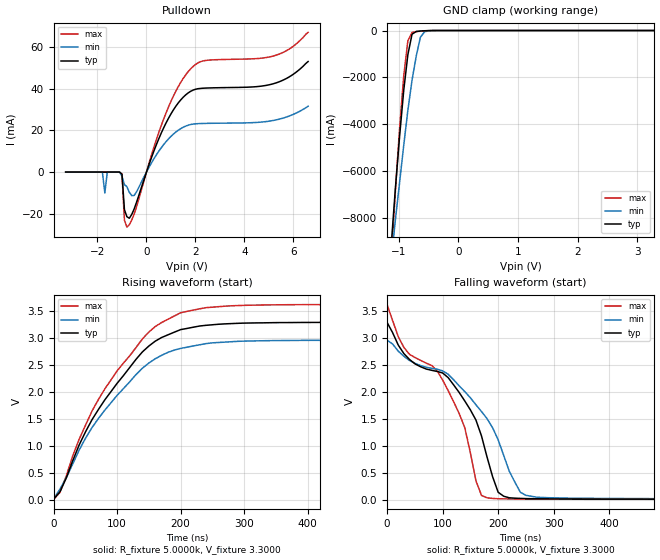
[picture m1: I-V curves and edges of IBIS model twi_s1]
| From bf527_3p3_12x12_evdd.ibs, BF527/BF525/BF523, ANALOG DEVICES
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|   Model ptwi400kv123
[Model]   twi_s1
Model_type I/O_open_drain
Polarity   Non-Inverting
Enable   Active-Low
Vinl =   0.9900V
Vinh =   2.3100V
Vmeas =  1.6500V
Cref =   50.0000pF
Rref =   5.0000k
Vref =   3.3000V
C_comp   7.1300pF   6.4200pF   7.8500pF
[Temperature Range]   25.0000   0.1250k   0.0
[Voltage Range]   3.3000V   2.9700V   3.6300V
[Pullup Reference]   3.3000V   2.9700V   3.6300V
[Pulldown Reference]   0.0V   0.0V   0.0V
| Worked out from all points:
|   slope of the pulldown table from 0 to 0.495 V, typ, clamps not added: 31.4 ohm
|   GND clamp passes 1 mA (typ) near -0.44 V on its own axis
|   rising waveform, R_fixture 5.0000k, V_fixture 3.3000: 20-80 % time 104ns typ, 106ns min, 107ns max; typ from 0.019 V to 3.3 V
|   falling waveform, R_fixture 5.0000k, V_fixture 3.3000: 20-80 % time 146ns typ, 114ns min, 126ns max; typ from 3.3 V to 0.019 V
[Pulldown]
|Voltage   I(typ)   I(min)   I(max)
-3.3V     0A         0A         0A
-1.8V     0A         0A         0A
-1.7V     0A         -10mA      0A
-1.6V     0A         0A         0A
-1V       -1mA       -2mA       -1mA
-900mV    -18mA      -6mA       -23mA
-800mV    -21.4mA    -7mA       -26.4mA
-500mV    -17.59mA   -11.2mA    -20.02mA
800mV     23.57mA    14.59mA    28.39mA
1.8V      38.7mA     22.79mA    49.44mA
5.1V      42.1mA     24.59mA    55.41mA
6.6V      53mA       31.57mA    67mA
[GND_clamp]
|Voltage   I(typ)   I(min)   I(max)
-3.3V     -90.22A    -67.03A    -109.2A
-1.13V    -9.15A     -9.802A    -9.773A
-1.06V    -6.741A    -8.07A     -6.847A
-990mV    -4.542A    -6.502A    -4.203A
-920mV    -2.558A    -4.904A    -1.946A
-850mV    -1.03A     -3.397A    -436.4mA
-780mV    -157.1mA   -2.116A    -83.33mA
-710mV    -41.57mA   -1.097A    -46.35mA
-640mV    -20.93mA   -289.8mA   -29.13mA
-570mV    -10.16mA   -55.23mA   -15.76mA
-500mV    -3.553mA   -11.78mA   -6.312mA
3.28V     9.333nA    34.31nA    22.33nA
[Ramp]
| variable   typ   min   max
dV/dt_r  1.9683/0.1040u   1.7657/0.1065u   2.1669/0.1069u
dV/dt_f  1.9682/0.1464u   1.7655/0.1144u   2.1669/0.1264u
R_load = 5.0000k
[Rising Waveform]
R_fixture= 5.0000k
V_fixture= 3.3000
V_fixture_min= 2.9700
V_fixture_max= 3.6300
L_fixture= 0.0H
C_fixture= 0.0F
|time   V(typ)   V(min)   V(max)
0s        18.51mV    26.09mV    17.45mV
10.1ns    156.9mV    206.3mV    144.4mV
40.4ns    1.026V     931.6mV    1.132V
60.61ns   1.494V     1.347V     1.654V
100ns     2.166V     1.943V     2.397V
150ns     2.858V     2.543V     3.117V
200ns     3.163V     2.815V     3.475V
240ns     3.243V     2.904V     3.57V
330ns     3.289V     2.957V     3.62V
1us       3.299V     2.969V     3.629V
[Falling Waveform]
R_fixture= 5.0000k
V_fixture= 3.3000
V_fixture_min= 2.9700
V_fixture_max= 3.6300
L_fixture= 0.0H
C_fixture= 0.0F
|time   V(typ)   V(min)   V(max)
0s        3.299V     2.969V     3.629V
30.3ns    2.719V     2.67V      2.834V
110ns     2.274V     2.336V     2.034V
140ns     1.839V     2.013V     1.343V
160ns     1.487V     1.77V      361.3mV
180ns     800.6mV    1.513V     45.17mV
200ns     148.5mV    1.121V     28.15mV
220ns     46.22mV    538.2mV    24.99mV
250ns     30.66mV    91.34mV    21.99mV
1us       18.65mV    26.53mV    17.55mV
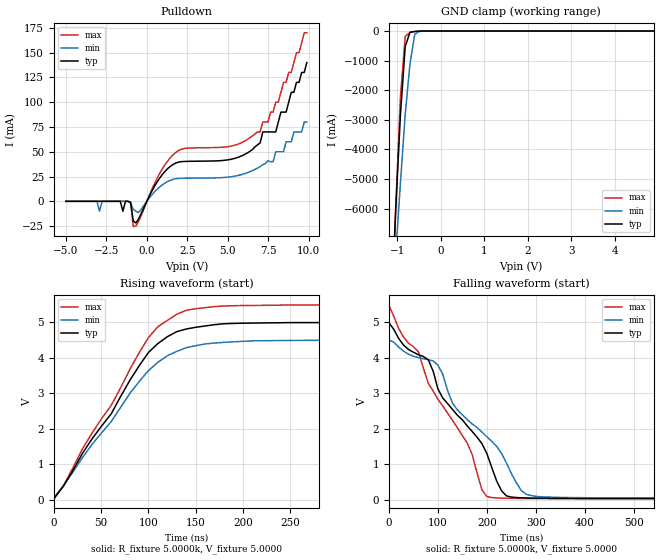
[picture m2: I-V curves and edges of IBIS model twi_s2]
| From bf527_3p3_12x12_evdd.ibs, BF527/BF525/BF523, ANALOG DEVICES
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[Model]   twi_s2
Model_type I/O_open_drain
Polarity   Non-Inverting
Enable   Active-Low
Vinl =   1.5000V
Vinh =   3.5000V
Vmeas =  2.5000V
Cref =   50.0000pF
Rref =   5.0000k
Vref =   5.0000V
C_comp   7.1300pF   6.4200pF   7.8500pF
[Temperature Range]   25.0000   0.1250k   0.0
[Voltage Range]   5.0000V   4.5000V   5.5000V
[Pullup Reference]   5.0000V   4.5000V   5.5000V
[Pulldown Reference]   0.0V   0.0V   0.0V
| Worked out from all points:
|   slope of the pulldown table from 0 to 0.75 V, typ, clamps not added: 33.5 ohm
|   GND clamp passes 1 mA (typ) near -0.41 V on its own axis
|   rising waveform, R_fixture 5.0000k, V_fixture 5.0000: 20-80 % time 71.7ns typ, 74.9ns min, 71.7ns max; typ from 0.028 V to 5 V
|   falling waveform, R_fixture 5.0000k, V_fixture 5.0000: 20-80 % time 133ns typ, 136ns min, 131ns max; typ from 5 V to 0.028 V
[Pulldown]
|Voltage   I(typ)   I(min)   I(max)
-5V       0A         0A         0A
-3.08V    0A         0A         0A
-2.92V    0A         -10mA      0A
-1.48V    -10mA      0A         0A
-1.16V    0A         0A         0A
-680mV    -21.84mA   -10mA      -24.85mA
760mV     22.63mA    14.03mA    27.21mA
1.88V     39.19mA    22.97mA    50.38mA
5.24V     42.56mA    24.89mA    55.85mA
7V        59mA       35mA       70mA
7.96V     70mA       50mA       100mA
9.88V     140mA      80mA       170mA
[GND_clamp]
|Voltage   I(typ)   I(min)   I(max)
-5V       -154.8A    -112.6A    -188.3A
-1.15V    -9.852A    -10.3A     -10.62A
-1.04V    -6.072A    -7.584A    -6.041A
-930mV    -2.823A    -5.131A    -2.23A
-820mV    -522mA     -2.814A    -178.4mA
-710mV    -41.57mA   -1.097A    -46.35mA
-600mV    -14.23mA   -109.6mA   -21.06mA
-490mV    -2.941mA   -9.414mA   -5.34mA
4.9V      652.3nA    550nA      1.064uA
[Ramp]
| variable   typ   min   max
dV/dt_r  2.9801/71.5841n   2.6744/75.0558n   3.2775/71.5341n
dV/dt_f  2.9806/0.1337u   2.6745/0.1359u   3.2775/0.1317u
R_load = 5.0000k
[Rising Waveform]
R_fixture= 5.0000k
V_fixture= 5.0000
V_fixture_min= 4.5000
V_fixture_max= 5.5000
L_fixture= 0.0H
C_fixture= 0.0F
|time   V(typ)   V(min)   V(max)
0s        28.11mV    39.66mV    26.48mV
10.1ns    376.6mV    399.7mV    388.8mV
40.4ns    1.714V     1.559V     1.878V
60.61ns   2.418V     2.199V     2.657V
80.81ns   3.385V     3.013V     3.697V
100ns     4.15V      3.639V     4.568V
110ns     4.402V     3.874V     4.878V
140ns     4.81V      4.284V     5.338V
230ns     4.984V     4.483V     5.48V
1us       4.995V     4.497V     5.489V
[Falling Waveform]
R_fixture= 5.0000k
V_fixture= 5.0000
V_fixture_min= 4.5000
V_fixture_max= 5.5000
L_fixture= 0.0H
C_fixture= 0.0F
|time   V(typ)   V(min)   V(max)
0s        4.996V     4.498V     5.489V
60.61ns   4.086V     4.002V     4.163V
80.81ns   3.941V     3.943V     3.274V
100ns     3.132V     3.794V     2.835V
130ns     2.541V     2.72V      2.236V
200ns     1.299V     1.77V      86.97mV
240ns     105.5mV    1.034V     39.25mV
270ns     52.18mV    258.9mV    33.25mV
300ns     42.03mV    90.55mV    31.18mV
1us       28.31mV    40.48mV    26.54mV
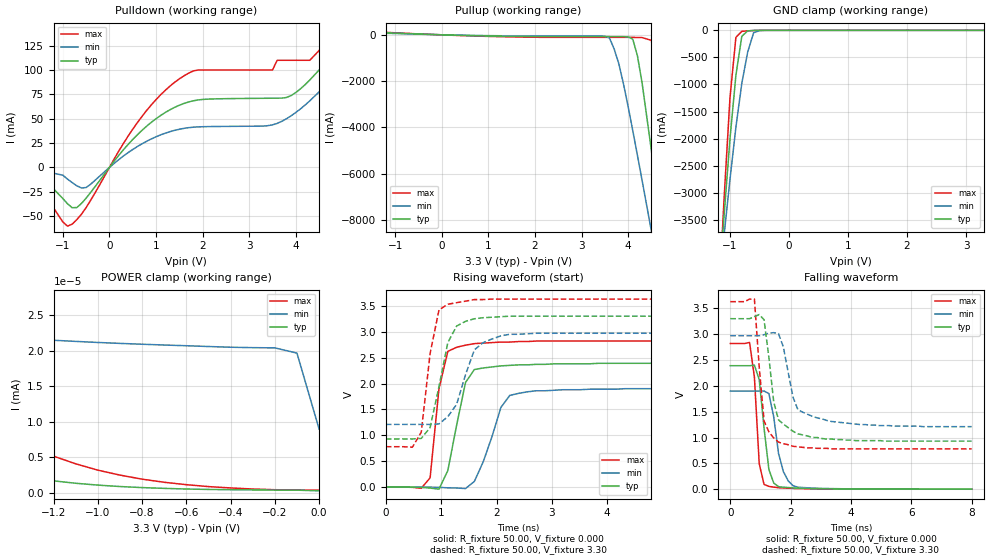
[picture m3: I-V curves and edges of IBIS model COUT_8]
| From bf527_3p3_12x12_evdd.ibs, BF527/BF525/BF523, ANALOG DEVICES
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|   Model prw0408swcdg_25
[Model]   COUT_8
Model_type   I/O
Polarity   Non-Inverting
Enable   Active-Low
Vinl =   0.40V
Vinh =   2.40V
Vmeas =   1.20V
Cref =  50.00pF
Rref =   1.00M
Vref =  0.000V
C_comp   4.60pF   4.14pF   5.06pF
[Temperature Range]   25.00   0.12k   -40.00
[Voltage Range]   3.30V   2.97V   3.63V
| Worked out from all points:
|   slope of the pulldown table from 0 to 0.495 V, typ, clamps not added: 17.4 ohm
|   slope of the pullup table from 0 to 0.495 V, typ, clamps not added: 17.2 ohm
|   GND clamp passes 1 mA (typ) near -0.53 V on its own axis
|   POWER clamp passes 1 mA (typ) near -3.01 V on its own axis
|   rising waveform, R_fixture 50.00, V_fixture 0.000: 20-80 % time 270ps typ, 361ps min, 203ps max; typ from 0 V to 2.39 V
|   rising waveform, R_fixture 50.00, V_fixture 3.30: 20-80 % time 287ps typ, 335ps min, 221ps max; typ from 0.93 V to 3.3 V
|   falling waveform, R_fixture 50.00, V_fixture 0.000: 20-80 % time 265ps typ, 344ps min, 173ps max; typ from 2.39 V to 0 V
|   falling waveform, R_fixture 50.00, V_fixture 3.30: 20-80 % time 351ps typ, 422ps min, 240ps max; typ from 3.3 V to 0.93 V
[Pulldown]
| voltage   I(typ)   I(min)   I(max)
-3.3V     0A         0A         0A
-1.7V     0A         0A         -10mA
-900mV    -37.3mA    -12mA      -60.3mA
-500mV    -31.56mA   -20.64mA   -41.25mA
700mV     38.11mA    24.26mA    52.44mA
1.7V      67.22mA    40.81mA    96.76mA
3.9V      73.78mA    52.99mA    110mA
4.3V      89.73mA    68.32mA    110mA
5.1V      140mA      110mA      170mA
5.5V      170mA      59.39mA    210mA
6.1V      130mA      60.53mA    270mA
6.6V      900mA      68.68mA    3.72A
[Pullup]
| voltage   I(typ)   I(min)   I(max)
-3.3V     29.4mA     8.69mA     100mA
-2.5V     150mA      14.55mA    190mA
3.6V      -78.87mA   -140mA     -110mA
3.8V      -79.53mA   -1.25A     -110mA
4.1V      -190mA     -4.14A     -110mA
4.2V      -910mA     -5.21A     -120mA
4.3V      -2.08A     -6.29A     -120mA
4.5V      -5A        -8.48A     -240mA
4.7V      -8.09A     -10.68A    -3.22A
4.9V      -11.24A    -12.9A     -7.47A
5.1V      -14.4A     -15.12A    -11.86A
6.6V      -38.32A    -31.88A    -44.78A
[GND_clamp]
| voltage   I(typ)   I(min)   I(max)
-3.3V     -38.23A    -28.13A    -52.07A
-1.2V     -4.92A     -4.84A     -5.19A
-1.1V     -3.42A     -3.78A     -3.1A
-1V       -2A        -2.75A     -1.24A
-900mV    -830mA     -1.79A     -130mA
-800mV    -110mA     -980mA     -19.34mA
-700mV    -10.17mA   -400mA     -9.85mA
-600mV    -2.61mA    -45.18mA   -3.52mA
-500mV    -460uA     -4.57mA    -550uA
3.3V      270pA      20.45nA    210pA
[POWER_clamp]
| voltage   I(typ)   I(min)   I(max)
-3.3V     770mA      230nA      7.24A
-2.6V     27.11nA    32.42nA    2.22mA
-2.4V     19.51nA    28.98nA    180nA
-2.1V     11.42nA    25.47nA    30.02nA
-2V       9.44nA     24.65nA    25.41nA
-1.7V     5.12nA     22.9nA     14.8nA
-1.5V     3.3nA      22.17nA    9.95nA
-1.3V     2.1nA      21.67nA    6.47nA
-800mV    730pA      20.92nA    1.92nA
-200mV    380pA      20.41nA    430pA
-100mV    370pA      19.67nA    390pA
0V        270pA      8.98nA     360pA
[Ramp]
| variable   typ   min   max
dV/dt_r   1.43/0.21n   1.14/0.34n   1.69/0.14n
dV/dt_f   1.42/0.33n   1.06/0.46n   1.71/0.21n
R_load = 50.00
[Rising Waveform]
R_fixture = 50.00
V_fixture = 0.000
V_fixture_min = 0.000
V_fixture_max = 0.000
L_fixture = 0.000H
C_fixture = 0.000F
| time   V(typ)   V(min)   V(max)
0s        0V         0V         0V
800ps     -18.52mV   -880uV     180mV
960ps     -39.4mV    -4.85mV    1.9V
1.12ns    320mV      -13.43mV   2.62V
1.28ns    1.2V       -17.16mV   2.7V
1.44ns    2.02V      -27.53mV   2.74V
1.6ns     2.27V      110mV      2.77V
2.08ns    2.34V      1.54V      2.8V
2.24ns    2.35V      1.77V      2.8V
8ns       2.39V      1.9V       2.82V
[Rising Waveform]
R_fixture = 50.00
V_fixture = 3.30
V_fixture_min = 2.97
V_fixture_max = 3.63
L_fixture = 0.000H
C_fixture = 0.000F
| time   V(typ)   V(min)   V(max)
0s        930mV      1.21V      780mV
480ps     930mV      1.21V      770mV
640ps     940mV      1.21V      1.06V
800ps     1.15V      1.21V      2.58V
960ps     1.94V      1.22V      3.42V
1.12ns    2.79V      1.36V      3.53V
1.28ns    3.11V      1.6V       3.56V
1.6ns     3.25V      2.65V      3.62V
2.08ns    3.29V      2.92V      3.63V
8ns       3.3V       2.97V      3.63V
[Falling Waveform]
R_fixture = 50.00
V_fixture = 0.000
V_fixture_min = 0.000
V_fixture_max = 0.000
L_fixture = 0.000H
C_fixture = 0.000F
| time   V(typ)   V(min)   V(max)
0s        2.39V      1.9V       2.82V
640ps     2.39V      1.9V       2.84V
800ps     2.4V       1.9V       2.17V
960ps     2.12V      1.9V       490mV
1.12ns    1.18V      1.9V       91.85mV
1.28ns    380mV      1.85V      54.33mV
1.44ns    120mV      1.4V       39.26mV
1.76ns    38.11mV    340mV      23.2mV
2.08ns    23.9mV     67.58mV    15.25mV
8ns       15.47uV    140uV      4.83uV
[Falling Waveform]
R_fixture = 50.00
V_fixture = 3.30
V_fixture_min = 2.97
V_fixture_max = 3.63
L_fixture = 0.000H
C_fixture = 0.000F
| time   V(typ)   V(min)   V(max)
0s        3.3V       2.97V      3.63V
800ps     3.34V      2.97V      3.68V
1.12ns    3.28V      2.99V      1.32V
1.44ns    1.69V      3.03V      990mV
1.6ns     1.34V      3.01V      910mV
1.76ns    1.26V      2.75V      880mV
2.08ns    1.12V      1.78V      830mV
2.4ns     1.05V      1.49V      810mV
4.32ns    940mV      1.25V      780mV
8ns       930mV      1.21V      780mV
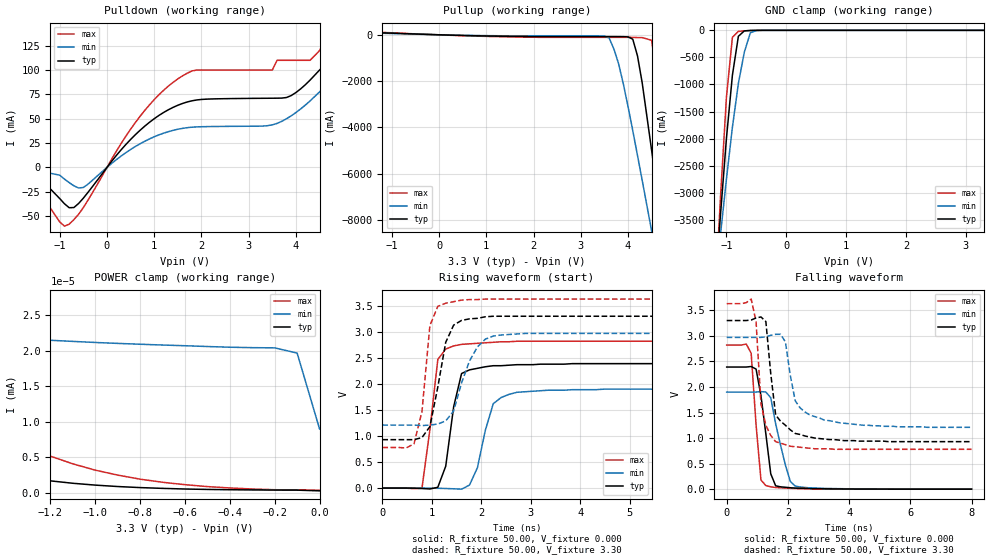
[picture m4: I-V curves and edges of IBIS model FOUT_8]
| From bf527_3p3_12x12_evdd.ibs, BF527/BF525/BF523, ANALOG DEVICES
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|   Model prw0408swcdg_3v_25
[Model]   FOUT_8
Model_type   I/O
Polarity   Non-Inverting
Enable   Active-Low
Vinl =   0.40V
Vinh =   2.40V
Vmeas =   1.20V
Cref =  50.00pF
Rref =   1.00M
Vref =  0.000V
C_comp   4.85pF   4.36pF   5.33pF
[Temperature Range]   25.00   0.12k   -40.00
[Voltage Range]   3.30V   2.97V   3.63V
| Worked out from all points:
|   slope of the pulldown table from 0 to 0.495 V, typ, clamps not added: 17.4 ohm
|   slope of the pullup table from 0 to 0.495 V, typ, clamps not added: 17.2 ohm
|   GND clamp passes 1 mA (typ) near -0.53 V on its own axis
|   POWER clamp passes 1 mA (typ) near -3.01 V on its own axis
|   rising waveform, R_fixture 50.00, V_fixture 0.000: 20-80 % time 240ps typ, 293ps min, 214ps max; typ from 0 V to 2.39 V
|   rising waveform, R_fixture 50.00, V_fixture 3.30: 20-80 % time 285ps typ, 401ps min, 185ps max; typ from 0.93 V to 3.3 V
|   falling waveform, R_fixture 50.00, V_fixture 0.000: 20-80 % time 309ps typ, 440ps min, 217ps max; typ from 2.39 V to 0 V
|   falling waveform, R_fixture 50.00, V_fixture 3.30: 20-80 % time 310ps typ, 472ps min, 260ps max; typ from 3.3 V to 0.93 V
[Pulldown]
| voltage   I(typ)   I(min)   I(max)
-3.3V     0A         0A         0A
-1.7V     0A         0A         -10mA
-900mV    -37.3mA    -12mA      -60.3mA
-500mV    -31.56mA   -20.64mA   -41.25mA
700mV     38.11mA    24.26mA    52.44mA
1.7V      67.22mA    40.81mA    96.76mA
3.9V      73.78mA    52.99mA    110mA
4.3V      89.73mA    68.32mA    110mA
5.1V      140mA      110mA      170mA
5.5V      170mA      59.39mA    210mA
6.1V      130mA      60.53mA    270mA
6.6V      900mA      68.68mA    3.72A
[Pullup]
| voltage   I(typ)   I(min)   I(max)
-3.3V     29.4mA     8.69mA     100mA
-2.5V     150mA      14.55mA    190mA
3.6V      -78.87mA   -140mA     -110mA
3.8V      -79.53mA   -1.25A     -110mA
4.1V      -190mA     -4.14A     -110mA
4.2V      -910mA     -5.21A     -120mA
4.3V      -2.08A     -6.29A     -120mA
4.5V      -5A        -8.48A     -240mA
4.7V      -8.09A     -10.68A    -3.22A
4.9V      -11.24A    -12.9A     -7.47A
5.1V      -14.4A     -15.12A    -11.86A
6.6V      -38.32A    -31.88A    -44.78A
[GND_clamp]
| voltage   I(typ)   I(min)   I(max)
-3.3V     -38.23A    -28.13A    -52.07A
-1.2V     -4.92A     -4.84A     -5.19A
-1.1V     -3.42A     -3.78A     -3.1A
-1V       -2A        -2.75A     -1.24A
-900mV    -830mA     -1.79A     -130mA
-800mV    -110mA     -980mA     -19.34mA
-700mV    -10.17mA   -400mA     -9.85mA
-600mV    -2.61mA    -45.18mA   -3.52mA
-500mV    -460uA     -4.57mA    -550uA
3.3V      270pA      20.45nA    210pA
[POWER_clamp]
| voltage   I(typ)   I(min)   I(max)
-3.3V     770mA      230nA      7.24A
-2.6V     27.11nA    32.42nA    2.22mA
-2.4V     19.51nA    28.98nA    180nA
-2.1V     11.42nA    25.47nA    30.02nA
-2V       9.44nA     24.65nA    25.41nA
-1.7V     5.12nA     22.9nA     14.8nA
-1.5V     3.3nA      22.17nA    9.95nA
-1.3V     2.1nA      21.67nA    6.47nA
-800mV    730pA      20.92nA    1.92nA
-200mV    380pA      20.41nA    430pA
-100mV    370pA      19.67nA    390pA
0V        270pA      8.98nA     360pA
[Ramp]
| variable   typ   min   max
dV/dt_r   1.43/0.21n   1.14/0.35n   1.69/0.15n
dV/dt_f   1.42/0.31n   1.06/0.48n   1.71/0.21n
R_load = 50.00
[Rising Waveform]
R_fixture = 50.00
V_fixture = 0.000
V_fixture_min = 0.000
V_fixture_max = 0.000
L_fixture = 0.000H
C_fixture = 0.000F
| time   V(typ)   V(min)   V(max)
0s        0V         0V         0V
800ps     -8.44mV    -70.12uV   -2.49mV
1.12ns    15.09mV    -4.13mV    2.47V
1.28ns    420mV      -8.02mV    2.67V
1.44ns    1.56V      -13.76mV   2.73V
1.6ns     2.2V       -20.86mV   2.76V
1.92ns    2.3V       390mV      2.78V
2.24ns    2.35V      1.62V      2.8V
2.56ns    2.36V      1.8V       2.81V
8ns       2.39V      1.9V       2.82V
[Rising Waveform]
R_fixture = 50.00
V_fixture = 3.30
V_fixture_min = 2.97
V_fixture_max = 3.63
L_fixture = 0.000H
C_fixture = 0.000F
| time   V(typ)   V(min)   V(max)
0s        930mV      1.21V      780mV
640ps     930mV      1.21V      850mV
800ps     970mV      1.2V       1.47V
960ps     1.18V      1.21V      3.12V
1.12ns    1.94V      1.23V      3.49V
1.28ns    2.8V       1.29V      3.55V
1.44ns    3.13V      1.48V      3.58V
1.76ns    3.25V      2.44V      3.62V
2.24ns    3.3V       2.92V      3.63V
8ns       3.3V       2.97V      3.63V
[Falling Waveform]
R_fixture = 50.00
V_fixture = 0.000
V_fixture_min = 0.000
V_fixture_max = 0.000
L_fixture = 0.000H
C_fixture = 0.000F
| time   V(typ)   V(min)   V(max)
0s        2.39V      1.9V       2.82V
800ps     2.4V       1.9V       2.66V
960ps     2.35V      1.9V       1.26V
1.12ns    1.83V      1.91V      180mV
1.28ns    1.08V      1.9V       70.27mV
1.44ns    300mV      1.79V      45.97mV
1.6ns     66.01mV    1.28V      32.22mV
2.08ns    27.62mV    150mV      17.01mV
2.24ns    21.21mV    60.02mV    12.92mV
8ns       50.75uV    170uV      16.89uV
[Falling Waveform]
R_fixture = 50.00
V_fixture = 3.30
V_fixture_min = 2.97
V_fixture_max = 3.63
L_fixture = 0.000H
C_fixture = 0.000F
| time   V(typ)   V(min)   V(max)
0s        3.3V       2.97V      3.63V
800ps     3.31V      2.97V      3.72V
960ps     3.35V      2.97V      3.28V
1.12ns    3.37V      2.97V      1.67V
1.28ns    3.28V      2.98V      1.25V
1.6ns     1.45V      3.03V      930mV
1.92ns    1.25V      2.88V      870mV
2.24ns    1.09V      1.73V      830mV
2.72ns    1.02V      1.45V      800mV
8ns       930mV      1.21V      780mV
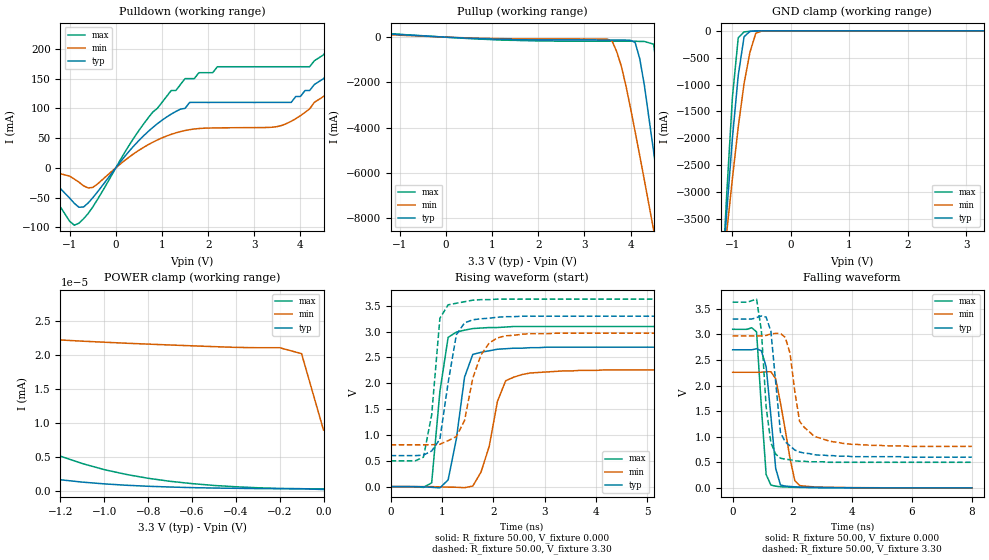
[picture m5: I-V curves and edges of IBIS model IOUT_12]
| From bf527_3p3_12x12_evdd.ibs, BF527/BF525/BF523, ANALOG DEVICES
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|   Model prw0812swcdg_25
[Model]   IOUT_12
Model_type   I/O
Polarity   Non-Inverting
Enable   Active-Low
Vinl =   0.40V
Vinh =   2.40V
Vmeas =   1.20V
Cref =  50.00pF
Rref =   1.00M
Vref =  0.000V
C_comp   4.38pF   3.94pF   4.82pF
[Temperature Range]   25.00   0.12k   -40.00
[Voltage Range]   3.30V   2.97V   3.63V
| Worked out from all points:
|   slope of the pulldown table from 0 to 0.495 V, typ, clamps not added: 10.9 ohm
|   slope of the pullup table from 0 to 0.495 V, typ, clamps not added: 10.8 ohm
|   GND clamp passes 1 mA (typ) near -0.53 V on its own axis
|   POWER clamp passes 1 mA (typ) near -3.01 V on its own axis
|   rising waveform, R_fixture 50.00, V_fixture 0.000: 20-80 % time 252ps typ, 328ps min, 208ps max; typ from 0 V to 2.7 V
|   rising waveform, R_fixture 50.00, V_fixture 3.30: 20-80 % time 257ps typ, 335ps min, 190ps max; typ from 0.6 V to 3.3 V
|   falling waveform, R_fixture 50.00, V_fixture 0.000: 20-80 % time 260ps typ, 414ps min, 214ps max; typ from 2.7 V to 0 V
|   falling waveform, R_fixture 50.00, V_fixture 3.30: 20-80 % time 262ps typ, 378ps min, 256ps max; typ from 3.3 V to 0.6 V
[Pulldown]
| voltage   I(typ)   I(min)   I(max)
-3.3V     0A         0A         0A
-2.1V     0A         0A         0A
-900mV    -59.7mA    -19mA      -96.5mA
-500mV    -50.5mA    -33.03mA   -66mA
600mV     53.68mA    34.3mA     73.6mA
1.5V      100mA      62.7mA     150mA
3.8V      110mA      78.23mA    170mA
5.1V      210mA      170mA      260mA
5.5V      260mA      93.56mA    320mA
5.9V      300mA      93.14mA    380mA
6.1V      200mA      95.36mA    410mA
6.6V      960mA      110mA      3.88A
[Pullup]
| voltage   I(typ)   I(min)   I(max)
-3.3V     42.4mA     12.36mA    140mA
-2.3V     220mA      140mA      260mA
3.6V      -130mA     -170mA     -180mA
3.8V      -130mA     -1.28A     -180mA
4.1V      -240mA     -4.18A     -180mA
4.2V      -960mA     -5.24A     -190mA
4.3V      -2.13A     -6.32A     -190mA
4.5V      -5.05A     -8.51A     -310mA
4.7V      -8.14A     -10.71A    -3.29A
4.9V      -11.28A    -12.93A    -7.53A
5.1V      -14.45A    -15.15A    -11.93A
6.6V      -38.37A    -31.91A    -44.86A
[GND_clamp]
| voltage   I(typ)   I(min)   I(max)
-3.3V     -38.23A    -28.13A    -52.07A
-1.2V     -4.92A     -4.84A     -5.19A
-1.1V     -3.42A     -3.78A     -3.1A
-1V       -2A        -2.75A     -1.24A
-900mV    -830mA     -1.79A     -130mA
-800mV    -110mA     -980mA     -19.34mA
-700mV    -10.17mA   -400mA     -9.85mA
-600mV    -2.61mA    -45.18mA   -3.52mA
-500mV    -460uA     -4.57mA    -550uA
3.3V      270pA      21.08nA    210pA
[POWER_clamp]
| voltage   I(typ)   I(min)   I(max)
-3.3V     770mA      230nA      7.24A
-2.7V     34.09nA    35.52nA    160mA
-2.6V     27.14nA    33.37nA    2.22mA
-2.4V     19.53nA    29.9nA     180nA
-2.3V     16.45nA    28.52nA    42.13nA
-2.1V     11.45nA    26.35nA    30.02nA
-1.7V     5.14nA     23.72nA    14.8nA
-1.3V     2.12nA     22.43nA    6.47nA
-800mV    750pA      21.61nA    1.92nA
-200mV    390pA      21.08nA    430pA
-100mV    390pA      20.21nA    390pA
0V        270pA      8.99nA     360pA
[Ramp]
| variable   typ   min   max
dV/dt_r   1.62/0.20n   1.36/0.32n   1.86/0.14n
dV/dt_f   1.62/0.27n   1.30/0.42n   1.88/0.22n
R_load = 50.00
[Rising Waveform]
R_fixture = 50.00
V_fixture = 0.000
V_fixture_min = 0.000
V_fixture_max = 0.000
L_fixture = 0.000H
C_fixture = 0.000F
| time   V(typ)   V(min)   V(max)
0s        0V         0V         0V
800ps     -13.46mV   -850uV     72.97mV
960ps     -24.1mV    -4.43mV    1.84V
1.12ns    130mV      -10.9mV    2.89V
1.28ns    920mV      -12.29mV   2.99V
1.44ns    2.12V      -20.87mV   3.03V
1.6ns     2.56V      10.64mV    3.06V
2.08ns    2.66V      1.65V      3.08V
2.4ns     2.68V      2.12V      3.1V
8ns       2.7V       2.26V      3.1V
[Rising Waveform]
R_fixture = 50.00
V_fixture = 3.30
V_fixture_min = 2.97
V_fixture_max = 3.63
L_fixture = 0.000H
C_fixture = 0.000F
| time   V(typ)   V(min)   V(max)
0s        600mV      810mV      500mV
640ps     610mV      810mV      570mV
800ps     690mV      810mV      1.39V
960ps     920mV      820mV      3.26V
1.12ns    2.01V      890mV      3.52V
1.28ns    2.94V      970mV      3.55V
1.44ns    3.17V      1.28V      3.58V
1.76ns    3.25V      2.55V      3.62V
2.08ns    3.28V      2.88V      3.63V
8ns       3.3V       2.97V      3.63V
[Falling Waveform]
R_fixture = 50.00
V_fixture = 0.000
V_fixture_min = 0.000
V_fixture_max = 0.000
L_fixture = 0.000H
C_fixture = 0.000F
| time   V(typ)   V(min)   V(max)
0s        2.7V       2.26V      3.1V
800ps     2.72V      2.26V      3.05V
960ps     2.68V      2.26V      1.59V
1.12ns    2.37V      2.27V      260mV
1.28ns    1.4V       2.27V      54.52mV
1.44ns    380mV      2.13V      32.27mV
1.6ns     55.65mV    1.66V      20.93mV
2.08ns    19.73mV    140mV      10.7mV
2.24ns    15.27mV    45.09mV    8.29mV
8ns       31.18uV    120uV      -980nV
[Falling Waveform]
R_fixture = 50.00
V_fixture = 3.30
V_fixture_min = 2.97
V_fixture_max = 3.63
L_fixture = 0.000H
C_fixture = 0.000F
| time   V(typ)   V(min)   V(max)
0s        3.3V       2.97V      3.63V
800ps     3.33V      2.97V      3.69V
960ps     3.36V      2.97V      3.08V
1.12ns    3.34V      2.98V      1.58V
1.28ns    3.06V      3.01V      880mV
1.6ns     1.08V      3.02V      580mV
1.92ns    820mV      2.63V      550mV
2.24ns    700mV      1.3V       520mV
2.72ns    650mV      1.01V      510mV
8ns       600mV      810mV      500mV
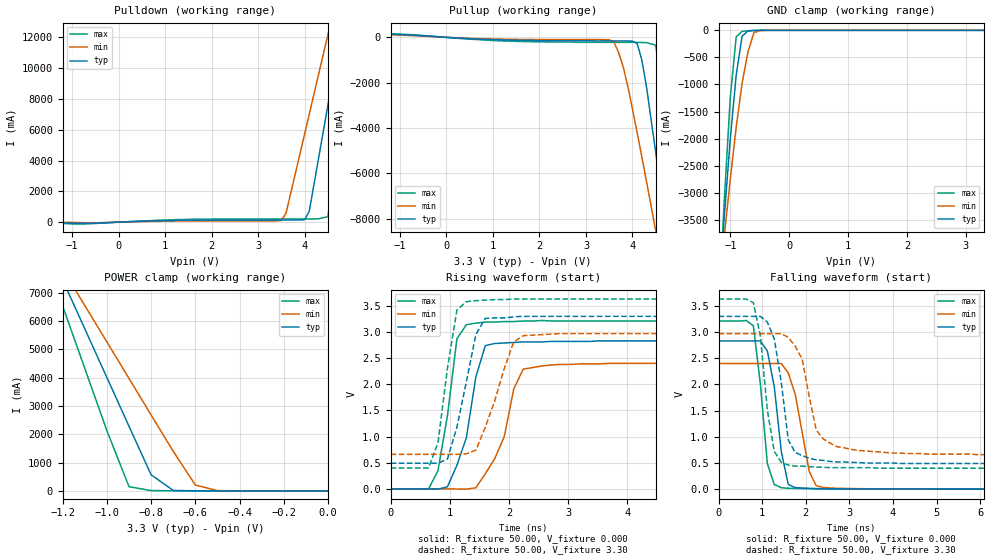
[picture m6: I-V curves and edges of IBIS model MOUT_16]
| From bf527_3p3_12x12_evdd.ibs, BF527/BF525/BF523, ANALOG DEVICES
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|   Model prw1216cdg_25
[Model]   MOUT_16
Model_type   I/O
Polarity   Non-Inverting
Enable   Active-Low
Vinl =   0.40V
Vinh =   2.40V
Vmeas =   1.20V
Cref =  50.00pF
Rref =   1.00M
Vref =  0.000V
C_comp   5.16pF   4.65pF   5.68pF
[Temperature Range]   25.00   0.12k   -40.00
[Voltage Range]   3.30V   2.97V   3.63V
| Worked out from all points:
|   slope of the pulldown table from 0 to 0.495 V, typ, clamps not added: 8.7 ohm
|   slope of the pullup table from 0 to 0.495 V, typ, clamps not added: 8.43 ohm
|   GND clamp passes 1 mA (typ) near -0.53 V on its own axis
|   POWER clamp passes 1 mA (typ) near -0.53 V on its own axis
|   rising waveform, R_fixture 50.00, V_fixture 0.000: 20-80 % time 318ps typ, 379ps min, 243ps max; typ from 0 V to 2.83 V
|   rising waveform, R_fixture 50.00, V_fixture 3.30: 20-80 % time 316ps typ, 406ps min, 239ps max; typ from 0.49 V to 3.3 V
|   falling waveform, R_fixture 50.00, V_fixture 0.000: 20-80 % time 272ps typ, 333ps min, 224ps max; typ from 2.83 V to 0 V
|   falling waveform, R_fixture 50.00, V_fixture 3.30: 20-80 % time 278ps typ, 345ps min, 268ps max; typ from 3.3 V to 0.49 V
[Pulldown]
| voltage   I(typ)   I(min)   I(max)
-3.3V     0A         0A         -10mA
-800mV    -82.8mA    -31.1mA    -120mA
1.3V      120mA      73.45mA    170mA
3.5V      140mA      110mA      210mA
3.6V      140mA      580mA      210mA
4V        160mA      5.73A      210mA
4.1V      710mA      7.01A      210mA
4.5V      7.59A      12.17A     360mA
4.7V      11.02A     14.75A     4.54A
4.9V      14.47A     17.33A     8.94A
5.1V      17.91A     19.91A     13.34A
6.6V      44.58A     39.34A     49.85A
[Pullup]
| voltage   I(typ)   I(min)   I(max)
-3.3V     300mA      300mA      320mA
1.2V      -120mA     -82.53mA   -160mA
3.6V      -160mA     -200mA     -220mA
3.8V      -160mA     -1.3A      -220mA
4.1V      -270mA     -4.2A      -220mA
4.2V      -990mA     -5.26A     -230mA
4.3V      -2.16A     -6.34A     -230mA
4.5V      -5.08A     -8.53A     -350mA
4.7V      -8.17A     -10.73A    -3.33A
4.9V      -11.31A    -12.95A    -7.57A
5.1V      -14.48A    -15.17A    -11.97A
6.6V      -38.4A     -31.93A    -44.89A
[GND_clamp]
| voltage   I(typ)   I(min)   I(max)
-3.3V     -38.23A    -28.13A    -52.07A
-1.2V     -4.92A     -4.84A     -5.19A
-1.1V     -3.42A     -3.78A     -3.1A
-1V       -2A        -2.75A     -1.24A
-900mV    -830mA     -1.79A     -120mA
-800mV    -110mA     -980mA     -19.28mA
-700mV    -10.13mA   -400mA     -9.8mA
-600mV    -2.59mA    -45.12mA   -3.5mA
-500mV    -460uA     -4.53mA    -550uA
3.3V      250pA      100uA      190pA
[POWER_clamp]
| voltage   I(typ)   I(min)   I(max)
-3.3V     44.38A     34.94A     59.98A
-1.3V     9.16A      9.12A      8.72A
-1.2V     7.44A      7.83A      6.52A
-1.1V     5.72A      6.54A      4.32A
-1V       4A         5.26A      2.12A
-900mV    2.28A      3.97A      150mA
-800mV    570mA      2.68A      11.94mA
-700mV    17.03mA    1.4A       5.58mA
-600mV    2.36mA     210mA      1.86mA
-500mV    460uA      11.86mA    260uA
0V        250pA      8.84nA     -1.69nA
[Ramp]
| variable   typ   min   max
dV/dt_r   1.70/0.25n   1.44/0.35n   1.93/0.21n
dV/dt_f   1.69/0.29n   1.39/0.41n   1.94/0.23n
R_load = 50.00
[Rising Waveform]
R_fixture = 50.00
V_fixture = 0.000
V_fixture_min = 0.000
V_fixture_max = 0.000
L_fixture = 0.000H
C_fixture = 0.000F
| time   V(typ)   V(min)   V(max)
0s        0V         0V         0V
640ps     -610uV     80.75uV    -4.69mV
800ps     -4.9mV     68.15uV    350mV
1.12ns    450mV      -2.13mV    2.87V
1.28ns    980mV      -5.72mV    3.14V
1.44ns    2.14V      20.7mV     3.17V
1.6ns     2.74V      290mV      3.19V
1.92ns    2.79V      1V         3.2V
2.24ns    2.81V      2.29V      3.21V
8ns       2.83V      2.4V       3.21V
[Rising Waveform]
R_fixture = 50.00
V_fixture = 3.30
V_fixture_min = 2.97
V_fixture_max = 3.63
L_fixture = 0.000H
C_fixture = 0.000F
| time   V(typ)   V(min)   V(max)
0s        490mV      660mV      400mV
640ps     490mV      660mV      400mV
800ps     490mV      660mV      880mV
960ps     570mV      660mV      2.31V
1.12ns    1.18V      660mV      3.42V
1.28ns    2.05V      670mV      3.58V
1.6ns     3.26V      1.18V      3.61V
2.08ns    3.29V      2.81V      3.63V
2.24ns    3.3V       2.93V      3.63V
8ns       3.3V       2.97V      3.63V
[Falling Waveform]
R_fixture = 50.00
V_fixture = 0.000
V_fixture_min = 0.000
V_fixture_max = 0.000
L_fixture = 0.000H
C_fixture = 0.000F
| time   V(typ)   V(min)   V(max)
0s        2.83V      2.4V       3.21V
800ps     2.83V      2.4V       3.12V
1.12ns    2.64V      2.4V       490mV
1.28ns    1.95V      2.4V       88.19mV
1.44ns    720mV      2.4V       27.85mV
1.6ns     89.32mV    2.22V      17.08mV
1.76ns    30.29mV    1.81V      13.63mV
2.08ns    15.75mV    340mV      8.53mV
2.24ns    11.81mV    67.26mV    6.38mV
8ns       22.21uV    110uV      9.25uV
[Falling Waveform]
R_fixture = 50.00
V_fixture = 3.30
V_fixture_min = 2.97
V_fixture_max = 3.63
L_fixture = 0.000H
C_fixture = 0.000F
| time   V(typ)   V(min)   V(max)
0s        3.3V       2.97V      3.63V
800ps     3.3V       2.97V      3.56V
960ps     3.3V       2.97V      2.93V
1.28ns    2.87V      2.97V      720mV
1.44ns    2.04V      2.97V      510mV
1.6ns     940mV      2.9V       460mV
1.76ns    700mV      2.73V      440mV
2.24ns    560mV      1.13V      420mV
2.72ns    520mV      810mV      410mV
8ns       490mV      660mV      400mV
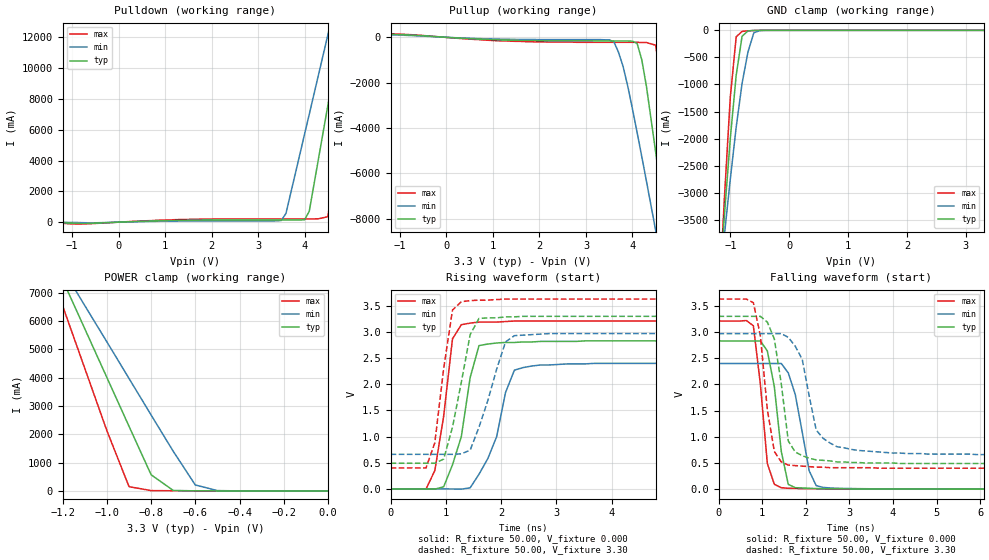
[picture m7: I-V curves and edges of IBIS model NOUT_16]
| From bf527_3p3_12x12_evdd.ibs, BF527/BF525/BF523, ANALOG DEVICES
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|   Model prw1216hcdg_25
[Model]   NOUT_16
Model_type   I/O
Polarity   Non-Inverting
Enable   Active-Low
Vinl =   0.40V
Vinh =   2.40V
Vmeas =   1.20V
Cref =  50.00pF
Rref =   1.00M
Vref =  0.000V
C_comp   5.17pF   4.65pF   5.69pF
[Temperature Range]   25.00   0.12k   -40.00
[Voltage Range]   3.30V   2.97V   3.63V
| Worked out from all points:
|   slope of the pulldown table from 0 to 0.495 V, typ, clamps not added: 8.7 ohm
|   slope of the pullup table from 0 to 0.495 V, typ, clamps not added: 8.43 ohm
|   GND clamp passes 1 mA (typ) near -0.52 V on its own axis
|   POWER clamp passes 1 mA (typ) near -0.53 V on its own axis
|   rising waveform, R_fixture 50.00, V_fixture 0.000: 20-80 % time 324ps typ, 403ps min, 242ps max; typ from 0 V to 2.83 V
|   rising waveform, R_fixture 50.00, V_fixture 3.30: 20-80 % time 316ps typ, 408ps min, 239ps max; typ from 0.49 V to 3.3 V
|   falling waveform, R_fixture 50.00, V_fixture 0.000: 20-80 % time 271ps typ, 335ps min, 224ps max; typ from 2.83 V to 0 V
|   falling waveform, R_fixture 50.00, V_fixture 3.30: 20-80 % time 276ps typ, 346ps min, 269ps max; typ from 3.3 V to 0.49 V
[Pulldown]
| voltage   I(typ)   I(min)   I(max)
-3.3V     0A         0A         -10mA
-800mV    -82.8mA    -31.1mA    -120mA
1.3V      120mA      73.45mA    170mA
3.5V      140mA      110mA      210mA
3.6V      140mA      580mA      210mA
4V        160mA      5.73A      210mA
4.1V      710mA      7.01A      210mA
4.5V      7.59A      12.17A     360mA
4.7V      11.02A     14.75A     4.54A
4.9V      14.47A     17.33A     8.94A
5.1V      17.91A     19.91A     13.34A
6.6V      44.58A     39.34A     49.85A
[Pullup]
| voltage   I(typ)   I(min)   I(max)
-3.3V     300mA      300mA      320mA
1.2V      -120mA     -82.55mA   -160mA
3.6V      -160mA     -200mA     -220mA
3.8V      -160mA     -1.3A      -220mA
4.1V      -270mA     -4.2A      -220mA
4.2V      -990mA     -5.26A     -230mA
4.3V      -2.16A     -6.34A     -230mA
4.5V      -5.08A     -8.53A     -350mA
4.7V      -8.17A     -10.73A    -3.33A
4.9V      -11.31A    -12.95A    -7.57A
5.1V      -14.48A    -15.17A    -11.97A
6.6V      -38.4A     -31.93A    -44.89A
[GND_clamp]
| voltage   I(typ)   I(min)   I(max)
-3.3V     -38.23A    -28.13A    -52.07A
-1.2V     -4.92A     -4.84A     -5.19A
-1.1V     -3.42A     -3.78A     -3.1A
-1V       -2A        -2.75A     -1.24A
-900mV    -830mA     -1.79A     -120mA
-800mV    -110mA     -980mA     -19.29mA
-700mV    -10.14mA   -400mA     -9.82mA
-600mV    -2.6mA     -45.13mA   -3.51mA
-500mV    -470uA     -4.54mA    -560uA
3.3V      250pA      110uA      -8.75uA
[POWER_clamp]
| voltage   I(typ)   I(min)   I(max)
-3.3V     44.38A     34.94A     59.98A
-1.3V     9.16A      9.12A      8.72A
-1.2V     7.44A      7.83A      6.52A
-1.1V     5.72A      6.54A      4.32A
-1V       4A         5.26A      2.12A
-900mV    2.28A      3.97A      150mA
-800mV    570mA      2.68A      11.96mA
-700mV    17.04mA    1.4A       5.6mA
-600mV    2.37mA     210mA      1.88mA
-500mV    470uA      11.87mA    270uA
0V        250pA      8.85nA     -34.3nA
[Ramp]
| variable   typ   min   max
dV/dt_r   1.70/0.26n   1.44/0.38n   1.93/0.21n
dV/dt_f   1.69/0.28n   1.39/0.41n   1.94/0.23n
R_load = 50.00
[Rising Waveform]
R_fixture = 50.00
V_fixture = 0.000
V_fixture_min = 0.000
V_fixture_max = 0.000
L_fixture = 0.000H
C_fixture = 0.000F
| time   V(typ)   V(min)   V(max)
0s        0V         0V         0V
640ps     -610uV     80.47uV    -4.68mV
800ps     -4.88mV    68.18uV    350mV
1.12ns    460mV      -2.12mV    2.87V
1.28ns    1V         -5.71mV    3.14V
1.44ns    2.13V      20.63mV    3.17V
1.6ns     2.74V      280mV      3.19V
1.92ns    2.79V      1V         3.19V
2.24ns    2.8V       2.27V      3.21V
8ns       2.83V      2.4V       3.21V
[Rising Waveform]
R_fixture = 50.00
V_fixture = 3.30
V_fixture_min = 2.97
V_fixture_max = 3.63
L_fixture = 0.000H
C_fixture = 0.000F
| time   V(typ)   V(min)   V(max)
0s        490mV      660mV      400mV
640ps     490mV      660mV      400mV
800ps     490mV      660mV      880mV
960ps     570mV      660mV      2.3V
1.12ns    1.18V      660mV      3.42V
1.28ns    2.04V      670mV      3.58V
1.6ns     3.26V      1.18V      3.61V
2.08ns    3.29V      2.81V      3.63V
2.24ns    3.29V      2.93V      3.63V
8ns       3.3V       2.97V      3.63V
[Falling Waveform]
R_fixture = 50.00
V_fixture = 0.000
V_fixture_min = 0.000
V_fixture_max = 0.000
L_fixture = 0.000H
C_fixture = 0.000F
| time   V(typ)   V(min)   V(max)
0s        2.83V      2.4V       3.21V
800ps     2.83V      2.4V       3.12V
1.12ns    2.64V      2.4V       490mV
1.28ns    1.96V      2.4V       94.05mV
1.44ns    720mV      2.4V       27.68mV
1.6ns     91.37mV    2.22V      16.8mV
1.76ns    28.44mV    1.81V      13.78mV
2.08ns    16.3mV     350mV      8.78mV
2.24ns    12.19mV    67.81mV    6.5mV
8ns       59.14uV    170uV      25.92uV
[Falling Waveform]
R_fixture = 50.00
V_fixture = 3.30
V_fixture_min = 2.97
V_fixture_max = 3.63
L_fixture = 0.000H
C_fixture = 0.000F
| time   V(typ)   V(min)   V(max)
0s        3.3V       2.97V      3.63V
800ps     3.3V       2.97V      3.56V
960ps     3.3V       2.97V      2.93V
1.28ns    2.87V      2.97V      720mV
1.44ns    2.01V      2.97V      520mV
1.6ns     920mV      2.9V       460mV
1.76ns    710mV      2.73V      450mV
2.24ns    560mV      1.13V      420mV
2.72ns    520mV      810mV      410mV
8ns       490mV      660mV      400mV
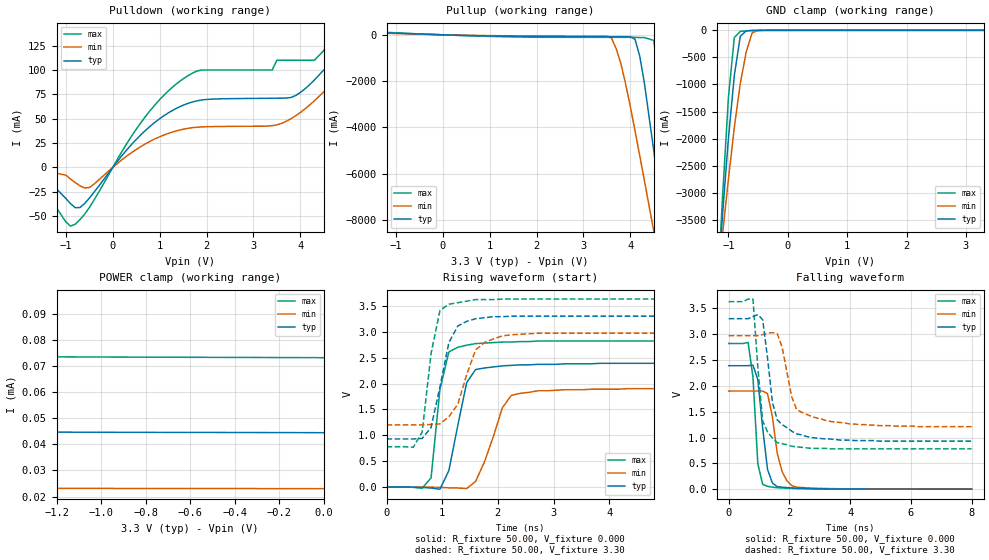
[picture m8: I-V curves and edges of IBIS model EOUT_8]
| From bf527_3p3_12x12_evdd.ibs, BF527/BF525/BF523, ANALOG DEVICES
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|   Model prwd0408swcdg_25
[Model]   EOUT_8
Model_type   I/O
Polarity   Non-Inverting
Enable   Active-Low
Vinl =   0.40V
Vinh =   2.40V
Vmeas =   1.20V
Cref =  50.00pF
Rref =   1.00M
Vref =  0.000V
C_comp   4.99pF   4.49pF   5.49pF
[Temperature Range]   25.00   0.12k   -40.00
[Voltage Range]   3.30V   2.97V   3.63V
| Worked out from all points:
|   slope of the pulldown table from 0 to 0.495 V, typ, clamps not added: 17.4 ohm
|   slope of the pullup table from 0 to 0.495 V, typ, clamps not added: 17.2 ohm
|   GND clamp passes 1 mA (typ) near -0.52 V on its own axis
|   POWER clamp passes 1 mA (typ) near -3.01 V on its own axis
|   rising waveform, R_fixture 50.00, V_fixture 0.000: 20-80 % time 270ps typ, 363ps min, 205ps max; typ from 0 V to 2.39 V
|   rising waveform, R_fixture 50.00, V_fixture 3.30: 20-80 % time 287ps typ, 339ps min, 222ps max; typ from 0.93 V to 3.3 V
|   falling waveform, R_fixture 50.00, V_fixture 0.000: 20-80 % time 265ps typ, 344ps min, 173ps max; typ from 2.39 V to 0 V
|   falling waveform, R_fixture 50.00, V_fixture 3.30: 20-80 % time 352ps typ, 422ps min, 240ps max; typ from 3.3 V to 0.93 V
[Pulldown]
| voltage   I(typ)   I(min)   I(max)
-3.3V     0A         0A         0A
-1.7V     0A         0A         -10mA
-900mV    -37.3mA    -12mA      -60.3mA
-500mV    -31.56mA   -20.63mA   -41.24mA
700mV     38.11mA    24.26mA    52.44mA
1.7V      67.21mA    40.81mA    96.76mA
3.9V      73.81mA    53.01mA    110mA
4.3V      89.76mA    68.34mA    110mA
5.1V      140mA      110mA      170mA
5.5V      170mA      59.59mA    210mA
6.1V      130mA      60.64mA    270mA
6.6V      900mA      68.79mA    3.73A
[Pullup]
| voltage   I(typ)   I(min)   I(max)
-3.3V     29.6mA     8.78mA     140mA
-2.5V     150mA      14.79mA    190mA
3.6V      -78.88mA   -140mA     -110mA
3.8V      -79.54mA   -1.25A     -110mA
4.1V      -190mA     -4.14A     -110mA
4.2V      -910mA     -5.21A     -120mA
4.3V      -2.08A     -6.29A     -120mA
4.5V      -5A        -8.48A     -240mA
4.7V      -8.09A     -10.68A    -3.22A
4.9V      -11.24A    -12.9A     -7.47A
5.1V      -14.4A     -15.12A    -11.86A
6.6V      -38.32A    -31.88A    -44.78A
[GND_clamp]
| voltage   I(typ)   I(min)   I(max)
-3.3V     -38.23A    -28.13A    -52.07A
-1.2V     -4.92A     -4.84A     -5.19A
-1.1V     -3.42A     -3.78A     -3.1A
-1V       -2A        -2.75A     -1.24A
-900mV    -830mA     -1.79A     -130mA
-800mV    -110mA     -980mA     -19.36mA
-700mV    -10.18mA   -400mA     -9.87mA
-600mV    -2.62mA    -45.19mA   -3.54mA
-500mV    -480uA     -4.58mA    -580uA
3.3V      44.45uA    23.04uA    73.04uA
[POWER_clamp]
| voltage   I(typ)   I(min)   I(max)
-3.3V     770mA      27.6uA     7.24A
-3.2V     190mA      26.92uA    5.97A
-3V       280uA      26.02uA    3.43A
-2.9V     54.42uA    25.63uA    2.16A
-2.8V     48.8uA     25.28uA    1A
-2.6V     47.56uA    24.68uA    2.3mA
-2.5V     47.08uA    24.43uA    94.39uA
-2.4V     46.67uA    24.21uA    76.8uA
-2.1V     45.72uA    23.7uA     75.16uA
-1.6V     44.91uA    23.26uA    73.88uA
-1.1V     44.64uA    23.12uA    73.46uA
0V        44.45uA    22.99uA    73.18uA
[Ramp]
| variable   typ   min   max
dV/dt_r   1.43/0.21n   1.14/0.34n   1.69/0.14n
dV/dt_f   1.42/0.33n   1.06/0.46n   1.71/0.21n
R_load = 50.00
[Rising Waveform]
R_fixture = 50.00
V_fixture = 0.000
V_fixture_min = 0.000
V_fixture_max = 0.000
L_fixture = 0.000H
C_fixture = 0.000F
| time   V(typ)   V(min)   V(max)
0s        0V         0V         0V
800ps     -18.5mV    -880uV     180mV
960ps     -39.35mV   -4.84mV    1.89V
1.12ns    320mV      -13.42mV   2.61V
1.28ns    1.19V      -17.15mV   2.7V
1.44ns    2.02V      -27.5mV    2.74V
1.6ns     2.27V      110mV      2.77V
2.08ns    2.34V      1.53V      2.8V
2.24ns    2.35V      1.77V      2.8V
8ns       2.39V      1.9V       2.82V
[Rising Waveform]
R_fixture = 50.00
V_fixture = 3.30
V_fixture_min = 2.97
V_fixture_max = 3.63
L_fixture = 0.000H
C_fixture = 0.000F
| time   V(typ)   V(min)   V(max)
0s        930mV      1.2V       780mV
480ps     930mV      1.2V       770mV
640ps     940mV      1.2V       1.06V
800ps     1.15V      1.21V      2.58V
960ps     1.94V      1.22V      3.41V
1.12ns    2.79V      1.36V      3.53V
1.28ns    3.11V      1.6V       3.56V
1.6ns     3.25V      2.65V      3.62V
2.08ns    3.29V      2.92V      3.63V
8ns       3.3V       2.97V      3.63V
[Falling Waveform]
R_fixture = 50.00
V_fixture = 0.000
V_fixture_min = 0.000
V_fixture_max = 0.000
L_fixture = 0.000H
C_fixture = 0.000F
| time   V(typ)   V(min)   V(max)
0s        2.39V      1.9V       2.82V
640ps     2.39V      1.9V       2.84V
800ps     2.4V       1.9V       2.17V
960ps     2.12V      1.9V       490mV
1.12ns    1.18V      1.9V       92.28mV
1.28ns    380mV      1.85V      54.43mV
1.44ns    120mV      1.4V       39.26mV
1.76ns    38.14mV    340mV      23.18mV
2.08ns    23.89mV    67.8mV     15.24mV
8ns       15.51uV    140uV      4.93uV
[Falling Waveform]
R_fixture = 50.00
V_fixture = 3.30
V_fixture_min = 2.97
V_fixture_max = 3.63
L_fixture = 0.000H
C_fixture = 0.000F
| time   V(typ)   V(min)   V(max)
0s        3.3V       2.97V      3.63V
800ps     3.34V      2.97V      3.68V
1.12ns    3.28V      2.99V      1.32V
1.44ns    1.68V      3.03V      990mV
1.6ns     1.34V      3.01V      900mV
1.76ns    1.25V      2.75V      880mV
2.08ns    1.12V      1.78V      830mV
2.4ns     1.05V      1.49V      810mV
4ns       950mV      1.26V      780mV
8ns       930mV      1.21V      780mV
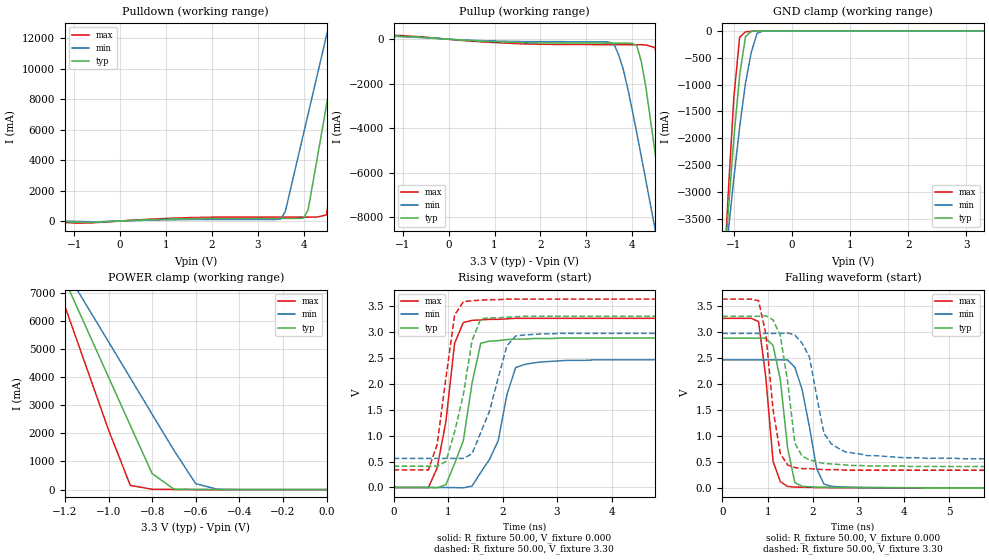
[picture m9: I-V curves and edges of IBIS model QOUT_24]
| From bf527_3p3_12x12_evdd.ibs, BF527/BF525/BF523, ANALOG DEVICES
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|   Model prw1624cdg_25
[Model]   QOUT_24
Model_type   I/O
Polarity   Non-Inverting
Enable   Active-Low
Vinl =   0.40V
Vinh =   2.40V
Vmeas =   1.20V
Cref =  50.00pF
Rref =   1.00M
Vref =  0.000V
C_comp   4.46pF   4.02pF   4.91pF
[Temperature Range]   25.00   0.12k   -40.00
[Voltage Range]   3.30V   2.97V   3.63V
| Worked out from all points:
|   slope of the pulldown table from 0 to 0.495 V, typ, clamps not added: 7.25 ohm
|   slope of the pullup table from 0 to 0.495 V, typ, clamps not added: 7.49 ohm
|   GND clamp passes 1 mA (typ) near -0.53 V on its own axis
|   POWER clamp passes 1 mA (typ) near -0.53 V on its own axis
|   rising waveform, R_fixture 50.00, V_fixture 0.000: 20-80 % time 339ps typ, 405ps min, 253ps max; typ from 0 V to 2.88 V
|   rising waveform, R_fixture 50.00, V_fixture 3.30: 20-80 % time 326ps typ, 425ps min, 253ps max; typ from 0.41 V to 3.3 V
|   falling waveform, R_fixture 50.00, V_fixture 0.000: 20-80 % time 261ps typ, 325ps min, 217ps max; typ from 2.88 V to 0 V
|   falling waveform, R_fixture 50.00, V_fixture 3.30: 20-80 % time 265ps typ, 320ps min, 257ps max; typ from 3.3 V to 0.41 V
[Pulldown]
| voltage   I(typ)   I(min)   I(max)
-3.3V     0A         0A         -10mA
-800mV    -99.3mA    -37.1mA    -140mA
1.6V      160mA      96.25mA    230mA
3.5V      170mA      130mA      250mA
3.6V      170mA      600mA      250mA
4V        190mA      5.74A      250mA
4.1V      740mA      7.03A      250mA
4.5V      7.61A      12.18A     400mA
4.7V      11.05A     14.76A     4.58A
4.9V      14.5A      17.34A     8.98A
5.1V      17.94A     19.93A     13.38A
6.6V      44.61A     39.37A     49.9A
[Pullup]
| voltage   I(typ)   I(min)   I(max)
-3.3V     340mA      340mA      390mA
1.6V      -150mA     -110mA     -210mA
3.6V      -180mA     -210mA     -250mA
3.8V      -180mA     -1.31A     -250mA
4.1V      -290mA     -4.21A     -250mA
4.2V      -1.01A     -5.28A     -250mA
4.3V      -2.18A     -6.36A     -260mA
4.5V      -5.1A      -8.54A     -380mA
4.7V      -8.19A     -10.75A    -3.35A
4.9V      -11.33A    -12.96A    -7.6A
5.1V      -14.5A     -15.19A    -12A
6.6V      -38.42A    -31.95A    -44.92A
[GND_clamp]
| voltage   I(typ)   I(min)   I(max)
-3.3V     -38.23A    -28.13A    -52.07A
-1.2V     -4.92A     -4.84A     -5.19A
-1.1V     -3.42A     -3.78A     -3.1A
-1V       -2A        -2.75A     -1.24A
-900mV    -830mA     -1.79A     -120mA
-800mV    -110mA     -980mA     -19.28mA
-700mV    -10.13mA   -400mA     -9.8mA
-600mV    -2.59mA    -45.12mA   -3.5mA
-500mV    -460uA     -4.53mA    -550uA
3.3V      250pA      100uA      190pA
[POWER_clamp]
| voltage   I(typ)   I(min)   I(max)
-3.3V     44.38A     34.94A     59.98A
-1.3V     9.16A      9.12A      8.72A
-1.2V     7.44A      7.83A      6.52A
-1.1V     5.72A      6.54A      4.32A
-1V       4A         5.26A      2.12A
-900mV    2.28A      3.97A      150mA
-800mV    570mA      2.68A      11.94mA
-700mV    17.03mA    1.4A       5.58mA
-600mV    2.36mA     210mA      1.86mA
-500mV    460uA      11.86mA    260uA
0V        250pA      8.84nA     -1.69nA
[Ramp]
| variable   typ   min   max
dV/dt_r   1.73/0.28n   1.48/0.38n   1.96/0.23n
dV/dt_f   1.73/0.27n   1.45/0.39n   1.98/0.22n
R_load = 50.00
[Rising Waveform]
R_fixture = 50.00
V_fixture = 0.000
V_fixture_min = 0.000
V_fixture_max = 0.000
L_fixture = 0.000H
C_fixture = 0.000F
| time   V(typ)   V(min)   V(max)
0s        0V         0V         0V
800ps     -6.08mV    56.38uV    380mV
960ps     53.93mV    -790uV     1.27V
1.12ns    460mV      -2.67mV    2.78V
1.28ns    900mV      -7.21mV    3.18V
1.6ns     2.78V      290mV      3.23V
1.92ns    2.83V      900mV      3.24V
2.24ns    2.86V      2.31V      3.26V
2.4ns     2.86V      2.37V      3.26V
8ns       2.88V      2.46V      3.26V
[Rising Waveform]
R_fixture = 50.00
V_fixture = 3.30
V_fixture_min = 2.97
V_fixture_max = 3.63
L_fixture = 0.000H
C_fixture = 0.000F
| time   V(typ)   V(min)   V(max)
0s        410mV      560mV      340mV
640ps     410mV      560mV      340mV
800ps     410mV      560mV      830mV
960ps     500mV      560mV      2.11V
1.12ns    1.07V      560mV      3.32V
1.28ns    1.79V      560mV      3.58V
1.44ns    2.83V      650mV      3.6V
1.6ns     3.25V      1.06V      3.61V
2.24ns    3.29V      2.92V      3.63V
8ns       3.3V       2.97V      3.63V
[Falling Waveform]
R_fixture = 50.00
V_fixture = 0.000
V_fixture_min = 0.000
V_fixture_max = 0.000
L_fixture = 0.000H
C_fixture = 0.000F
| time   V(typ)   V(min)   V(max)
0s        2.88V      2.46V      3.26V
800ps     2.88V      2.46V      3.2V
960ps     2.88V      2.46V      2.13V
1.12ns    2.74V      2.46V      510mV
1.28ns    2.08V      2.46V      120mV
1.44ns    770mV      2.46V      26.33mV
1.6ns     100mV      2.32V      14.86mV
2.08ns    13.99mV    370mV      7.21mV
2.24ns    10.49mV    74.58mV    5.46mV
8ns       16.41uV    86.7uV     3.2uV
[Falling Waveform]
R_fixture = 50.00
V_fixture = 3.30
V_fixture_min = 2.97
V_fixture_max = 3.63
L_fixture = 0.000H
C_fixture = 0.000F
| time   V(typ)   V(min)   V(max)
0s        3.3V       2.97V      3.63V
800ps     3.3V       2.97V      3.6V
960ps     3.31V      2.97V      2.97V
1.28ns    2.93V      2.97V      660mV
1.44ns    2.05V      2.98V      440mV
1.6ns     860mV      2.94V      390mV
1.76ns    610mV      2.78V      370mV
2.24ns    470mV      1.05V      350mV
2.72ns    440mV      690mV      340mV
8ns       410mV      560mV      340mV
